VERSION 5.8 ;
BUSBITCHARS "[]" ;
DIVIDERCHAR "/" ;
UNITS
    DATABASE MICRONS 1000 ;
END UNITS

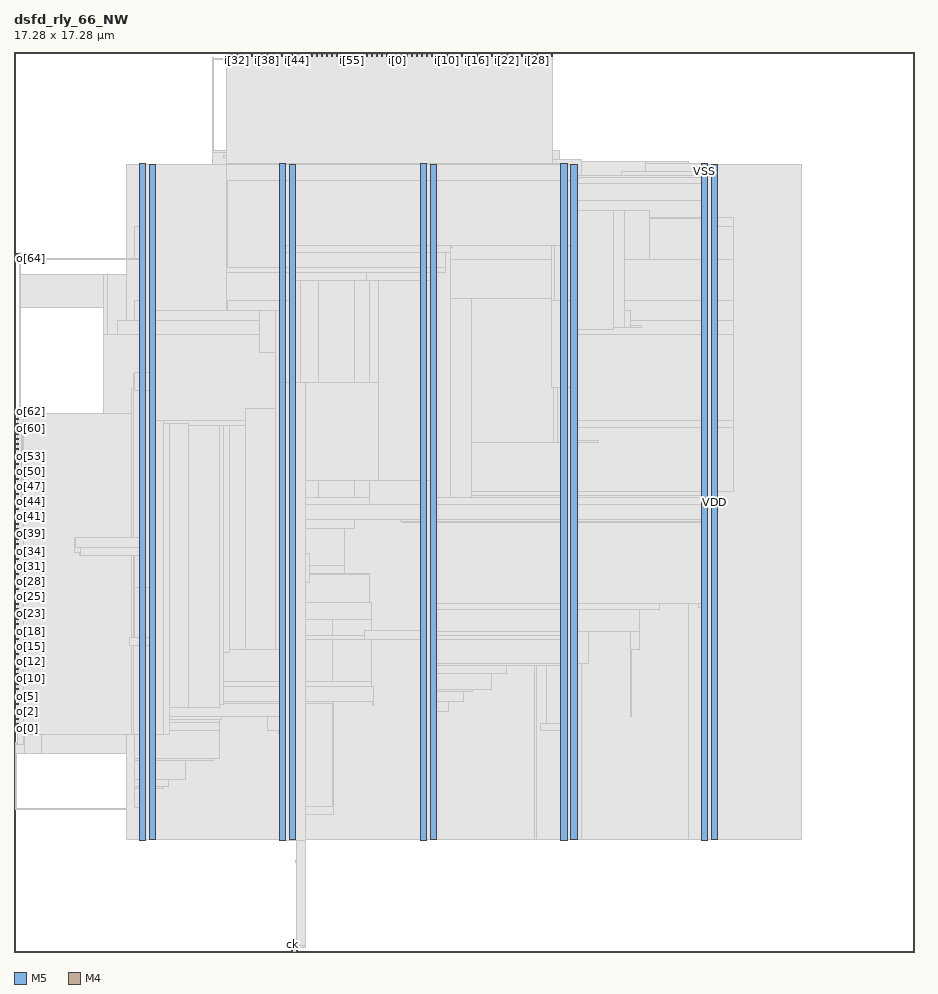
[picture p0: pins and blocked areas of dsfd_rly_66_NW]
MACRO dsfd_rly_66_NW
  FOREIGN dsfd_rly_66_NW 0 0 ;
  CLASS BLOCK ;
  SIZE 17.28 BY 17.28 ;
  PIN ck
    DIRECTION INPUT ;
    USE SIGNAL ;
    PORT
      LAYER M5 ;
        RECT  5.328 0 5.352 0.084 ;
    END
  END ck
  PIN i[0]
    DIRECTION INPUT ;
    USE SIGNAL ;
    PORT
      LAYER M5 ;
        RECT  7.344 17.196 7.368 17.28 ;
    END
  END i[0]
  PIN i[10]
    DIRECTION INPUT ;
    USE SIGNAL ;
    PORT
      LAYER M5 ;
        RECT  8.304 17.196 8.328 17.28 ;
    END
  END i[10]
  PIN i[11]
    DIRECTION INPUT ;
    USE SIGNAL ;
    PORT
      LAYER M5 ;
        RECT  8.4 17.196 8.424 17.28 ;
    END
  END i[11]
  PIN i[12]
    DIRECTION INPUT ;
    USE SIGNAL ;
    PORT
      LAYER M5 ;
        RECT  8.496 17.196 8.52 17.28 ;
    END
  END i[12]
  PIN i[13]
    DIRECTION INPUT ;
    USE SIGNAL ;
    PORT
      LAYER M5 ;
        RECT  8.592 17.196 8.616 17.28 ;
    END
  END i[13]
  PIN i[14]
    DIRECTION INPUT ;
    USE SIGNAL ;
    PORT
      LAYER M5 ;
        RECT  8.688 17.196 8.712 17.28 ;
    END
  END i[14]
  PIN i[15]
    DIRECTION INPUT ;
    USE SIGNAL ;
    PORT
      LAYER M5 ;
        RECT  8.784 17.196 8.808 17.28 ;
    END
  END i[15]
  PIN i[16]
    DIRECTION INPUT ;
    USE SIGNAL ;
    PORT
      LAYER M5 ;
        RECT  8.88 17.196 8.904 17.28 ;
    END
  END i[16]
  PIN i[17]
    DIRECTION INPUT ;
    USE SIGNAL ;
    PORT
      LAYER M5 ;
        RECT  8.976 17.196 9 17.28 ;
    END
  END i[17]
  PIN i[18]
    DIRECTION INPUT ;
    USE SIGNAL ;
    PORT
      LAYER M5 ;
        RECT  9.072 17.196 9.096 17.28 ;
    END
  END i[18]
  PIN i[19]
    DIRECTION INPUT ;
    USE SIGNAL ;
    PORT
      LAYER M5 ;
        RECT  9.168 17.196 9.192 17.28 ;
    END
  END i[19]
  PIN i[1]
    DIRECTION INPUT ;
    USE SIGNAL ;
    PORT
      LAYER M5 ;
        RECT  7.44 17.196 7.464 17.28 ;
    END
  END i[1]
  PIN i[20]
    DIRECTION INPUT ;
    USE SIGNAL ;
    PORT
      LAYER M5 ;
        RECT  9.264 17.196 9.288 17.28 ;
    END
  END i[20]
  PIN i[21]
    DIRECTION INPUT ;
    USE SIGNAL ;
    PORT
      LAYER M5 ;
        RECT  9.36 17.196 9.384 17.28 ;
    END
  END i[21]
  PIN i[22]
    DIRECTION INPUT ;
    USE SIGNAL ;
    PORT
      LAYER M5 ;
        RECT  9.456 17.196 9.48 17.28 ;
    END
  END i[22]
  PIN i[23]
    DIRECTION INPUT ;
    USE SIGNAL ;
    PORT
      LAYER M5 ;
        RECT  9.552 17.196 9.576 17.28 ;
    END
  END i[23]
  PIN i[24]
    DIRECTION INPUT ;
    USE SIGNAL ;
    PORT
      LAYER M5 ;
        RECT  9.648 17.196 9.672 17.28 ;
    END
  END i[24]
  PIN i[25]
    DIRECTION INPUT ;
    USE SIGNAL ;
    PORT
      LAYER M5 ;
        RECT  9.744 17.196 9.768 17.28 ;
    END
  END i[25]
  PIN i[26]
    DIRECTION INPUT ;
    USE SIGNAL ;
    PORT
      LAYER M5 ;
        RECT  9.84 17.196 9.864 17.28 ;
    END
  END i[26]
  PIN i[27]
    DIRECTION INPUT ;
    USE SIGNAL ;
    PORT
      LAYER M5 ;
        RECT  9.936 17.196 9.96 17.28 ;
    END
  END i[27]
  PIN i[28]
    DIRECTION INPUT ;
    USE SIGNAL ;
    PORT
      LAYER M5 ;
        RECT  10.032 17.196 10.056 17.28 ;
    END
  END i[28]
  PIN i[29]
    DIRECTION INPUT ;
    USE SIGNAL ;
    PORT
      LAYER M5 ;
        RECT  10.128 17.196 10.152 17.28 ;
    END
  END i[29]
  PIN i[2]
    DIRECTION INPUT ;
    USE SIGNAL ;
    PORT
      LAYER M5 ;
        RECT  7.536 17.196 7.56 17.28 ;
    END
  END i[2]
  PIN i[30]
    DIRECTION INPUT ;
    USE SIGNAL ;
    PORT
      LAYER M5 ;
        RECT  10.224 17.196 10.248 17.28 ;
    END
  END i[30]
  PIN i[31]
    DIRECTION INPUT ;
    USE SIGNAL ;
    PORT
      LAYER M5 ;
        RECT  10.32 17.196 10.344 17.28 ;
    END
  END i[31]
  PIN i[32]
    DIRECTION INPUT ;
    USE SIGNAL ;
    PORT
      LAYER M5 ;
        RECT  4.272 17.196 4.296 17.28 ;
    END
  END i[32]
  PIN i[33]
    DIRECTION INPUT ;
    USE SIGNAL ;
    PORT
      LAYER M5 ;
        RECT  4.368 17.196 4.392 17.28 ;
    END
  END i[33]
  PIN i[34]
    DIRECTION INPUT ;
    USE SIGNAL ;
    PORT
      LAYER M5 ;
        RECT  4.464 17.196 4.488 17.28 ;
    END
  END i[34]
  PIN i[35]
    DIRECTION INPUT ;
    USE SIGNAL ;
    PORT
      LAYER M5 ;
        RECT  4.56 17.196 4.584 17.28 ;
    END
  END i[35]
  PIN i[36]
    DIRECTION INPUT ;
    USE SIGNAL ;
    PORT
      LAYER M5 ;
        RECT  4.656 17.196 4.68 17.28 ;
    END
  END i[36]
  PIN i[37]
    DIRECTION INPUT ;
    USE SIGNAL ;
    PORT
      LAYER M5 ;
        RECT  4.752 17.196 4.776 17.28 ;
    END
  END i[37]
  PIN i[38]
    DIRECTION INPUT ;
    USE SIGNAL ;
    PORT
      LAYER M5 ;
        RECT  4.848 17.196 4.872 17.28 ;
    END
  END i[38]
  PIN i[39]
    DIRECTION INPUT ;
    USE SIGNAL ;
    PORT
      LAYER M5 ;
        RECT  4.944 17.196 4.968 17.28 ;
    END
  END i[39]
  PIN i[3]
    DIRECTION INPUT ;
    USE SIGNAL ;
    PORT
      LAYER M5 ;
        RECT  7.632 17.196 7.656 17.28 ;
    END
  END i[3]
  PIN i[40]
    DIRECTION INPUT ;
    USE SIGNAL ;
    PORT
      LAYER M5 ;
        RECT  5.04 17.196 5.064 17.28 ;
    END
  END i[40]
  PIN i[41]
    DIRECTION INPUT ;
    USE SIGNAL ;
    PORT
      LAYER M5 ;
        RECT  5.136 17.196 5.16 17.28 ;
    END
  END i[41]
  PIN i[42]
    DIRECTION INPUT ;
    USE SIGNAL ;
    PORT
      LAYER M5 ;
        RECT  5.232 17.196 5.256 17.28 ;
    END
  END i[42]
  PIN i[43]
    DIRECTION INPUT ;
    USE SIGNAL ;
    PORT
      LAYER M5 ;
        RECT  5.328 17.196 5.352 17.28 ;
    END
  END i[43]
  PIN i[44]
    DIRECTION INPUT ;
    USE SIGNAL ;
    PORT
      LAYER M5 ;
        RECT  5.424 17.196 5.448 17.28 ;
    END
  END i[44]
  PIN i[45]
    DIRECTION INPUT ;
    USE SIGNAL ;
    PORT
      LAYER M5 ;
        RECT  5.52 17.196 5.544 17.28 ;
    END
  END i[45]
  PIN i[46]
    DIRECTION INPUT ;
    USE SIGNAL ;
    PORT
      LAYER M5 ;
        RECT  5.616 17.196 5.64 17.28 ;
    END
  END i[46]
  PIN i[47]
    DIRECTION INPUT ;
    USE SIGNAL ;
    PORT
      LAYER M5 ;
        RECT  5.712 17.196 5.736 17.28 ;
    END
  END i[47]
  PIN i[48]
    DIRECTION INPUT ;
    USE SIGNAL ;
    PORT
      LAYER M5 ;
        RECT  5.808 17.196 5.832 17.28 ;
    END
  END i[48]
  PIN i[49]
    DIRECTION INPUT ;
    USE SIGNAL ;
    PORT
      LAYER M5 ;
        RECT  5.904 17.196 5.928 17.28 ;
    END
  END i[49]
  PIN i[4]
    DIRECTION INPUT ;
    USE SIGNAL ;
    PORT
      LAYER M5 ;
        RECT  7.728 17.196 7.752 17.28 ;
    END
  END i[4]
  PIN i[50]
    DIRECTION INPUT ;
    USE SIGNAL ;
    PORT
      LAYER M5 ;
        RECT  6 17.196 6.024 17.28 ;
    END
  END i[50]
  PIN i[51]
    DIRECTION INPUT ;
    USE SIGNAL ;
    PORT
      LAYER M5 ;
        RECT  6.096 17.196 6.12 17.28 ;
    END
  END i[51]
  PIN i[52]
    DIRECTION INPUT ;
    USE SIGNAL ;
    PORT
      LAYER M5 ;
        RECT  6.192 17.196 6.216 17.28 ;
    END
  END i[52]
  PIN i[53]
    DIRECTION INPUT ;
    USE SIGNAL ;
    PORT
      LAYER M5 ;
        RECT  6.288 17.196 6.312 17.28 ;
    END
  END i[53]
  PIN i[54]
    DIRECTION INPUT ;
    USE SIGNAL ;
    PORT
      LAYER M5 ;
        RECT  6.384 17.196 6.408 17.28 ;
    END
  END i[54]
  PIN i[55]
    DIRECTION INPUT ;
    USE SIGNAL ;
    PORT
      LAYER M5 ;
        RECT  6.48 17.196 6.504 17.28 ;
    END
  END i[55]
  PIN i[56]
    DIRECTION INPUT ;
    USE SIGNAL ;
    PORT
      LAYER M5 ;
        RECT  6.576 17.196 6.6 17.28 ;
    END
  END i[56]
  PIN i[57]
    DIRECTION INPUT ;
    USE SIGNAL ;
    PORT
      LAYER M5 ;
        RECT  6.672 17.196 6.696 17.28 ;
    END
  END i[57]
  PIN i[58]
    DIRECTION INPUT ;
    USE SIGNAL ;
    PORT
      LAYER M5 ;
        RECT  6.768 17.196 6.792 17.28 ;
    END
  END i[58]
  PIN i[59]
    DIRECTION INPUT ;
    USE SIGNAL ;
    PORT
      LAYER M5 ;
        RECT  6.864 17.196 6.888 17.28 ;
    END
  END i[59]
  PIN i[5]
    DIRECTION INPUT ;
    USE SIGNAL ;
    PORT
      LAYER M5 ;
        RECT  7.824 17.196 7.848 17.28 ;
    END
  END i[5]
  PIN i[60]
    DIRECTION INPUT ;
    USE SIGNAL ;
    PORT
      LAYER M5 ;
        RECT  6.96 17.196 6.984 17.28 ;
    END
  END i[60]
  PIN i[61]
    DIRECTION INPUT ;
    USE SIGNAL ;
    PORT
      LAYER M5 ;
        RECT  7.056 17.196 7.08 17.28 ;
    END
  END i[61]
  PIN i[62]
    DIRECTION INPUT ;
    USE SIGNAL ;
    PORT
      LAYER M5 ;
        RECT  7.152 17.196 7.176 17.28 ;
    END
  END i[62]
  PIN i[63]
    DIRECTION INPUT ;
    USE SIGNAL ;
    PORT
      LAYER M5 ;
        RECT  7.248 17.196 7.272 17.28 ;
    END
  END i[63]
  PIN i[64]
    DIRECTION INPUT ;
    USE SIGNAL ;
    PORT
      LAYER M5 ;
        RECT  4.08 17.196 4.104 17.28 ;
    END
  END i[64]
  PIN i[65]
    DIRECTION INPUT ;
    USE SIGNAL ;
    PORT
      LAYER M5 ;
        RECT  4.176 17.196 4.2 17.28 ;
    END
  END i[65]
  PIN i[6]
    DIRECTION INPUT ;
    USE SIGNAL ;
    PORT
      LAYER M5 ;
        RECT  7.92 17.196 7.944 17.28 ;
    END
  END i[6]
  PIN i[7]
    DIRECTION INPUT ;
    USE SIGNAL ;
    PORT
      LAYER M5 ;
        RECT  8.016 17.196 8.04 17.28 ;
    END
  END i[7]
  PIN i[8]
    DIRECTION INPUT ;
    USE SIGNAL ;
    PORT
      LAYER M5 ;
        RECT  8.112 17.196 8.136 17.28 ;
    END
  END i[8]
  PIN i[9]
    DIRECTION INPUT ;
    USE SIGNAL ;
    PORT
      LAYER M5 ;
        RECT  8.208 17.196 8.232 17.28 ;
    END
  END i[9]
  PIN o[0]
    DIRECTION OUTPUT ;
    USE SIGNAL ;
    PORT
      LAYER M4 ;
        RECT  0 4.272 0.084 4.296 ;
    END
  END o[0]
  PIN o[10]
    DIRECTION OUTPUT ;
    USE SIGNAL ;
    PORT
      LAYER M4 ;
        RECT  0 5.232 0.084 5.256 ;
    END
  END o[10]
  PIN o[11]
    DIRECTION OUTPUT ;
    USE SIGNAL ;
    PORT
      LAYER M4 ;
        RECT  0 5.328 0.084 5.352 ;
    END
  END o[11]
  PIN o[12]
    DIRECTION OUTPUT ;
    USE SIGNAL ;
    PORT
      LAYER M4 ;
        RECT  0 5.424 0.084 5.448 ;
    END
  END o[12]
  PIN o[13]
    DIRECTION OUTPUT ;
    USE SIGNAL ;
    PORT
      LAYER M4 ;
        RECT  0 5.52 0.084 5.544 ;
    END
  END o[13]
  PIN o[14]
    DIRECTION OUTPUT ;
    USE SIGNAL ;
    PORT
      LAYER M4 ;
        RECT  0 5.616 0.084 5.64 ;
    END
  END o[14]
  PIN o[15]
    DIRECTION OUTPUT ;
    USE SIGNAL ;
    PORT
      LAYER M4 ;
        RECT  0 5.712 0.084 5.736 ;
    END
  END o[15]
  PIN o[16]
    DIRECTION OUTPUT ;
    USE SIGNAL ;
    PORT
      LAYER M4 ;
        RECT  0 5.808 0.084 5.832 ;
    END
  END o[16]
  PIN o[17]
    DIRECTION OUTPUT ;
    USE SIGNAL ;
    PORT
      LAYER M4 ;
        RECT  0 5.904 0.084 5.928 ;
    END
  END o[17]
  PIN o[18]
    DIRECTION OUTPUT ;
    USE SIGNAL ;
    PORT
      LAYER M4 ;
        RECT  0 6 0.084 6.024 ;
    END
  END o[18]
  PIN o[19]
    DIRECTION OUTPUT ;
    USE SIGNAL ;
    PORT
      LAYER M4 ;
        RECT  0 6.096 0.084 6.12 ;
    END
  END o[19]
  PIN o[1]
    DIRECTION OUTPUT ;
    USE SIGNAL ;
    PORT
      LAYER M4 ;
        RECT  0 4.368 0.084 4.392 ;
    END
  END o[1]
  PIN o[20]
    DIRECTION OUTPUT ;
    USE SIGNAL ;
    PORT
      LAYER M4 ;
        RECT  0 6.192 0.084 6.216 ;
    END
  END o[20]
  PIN o[21]
    DIRECTION OUTPUT ;
    USE SIGNAL ;
    PORT
      LAYER M4 ;
        RECT  0 6.288 0.084 6.312 ;
    END
  END o[21]
  PIN o[22]
    DIRECTION OUTPUT ;
    USE SIGNAL ;
    PORT
      LAYER M4 ;
        RECT  0 6.384 0.084 6.408 ;
    END
  END o[22]
  PIN o[23]
    DIRECTION OUTPUT ;
    USE SIGNAL ;
    PORT
      LAYER M4 ;
        RECT  0 6.48 0.084 6.504 ;
    END
  END o[23]
  PIN o[24]
    DIRECTION OUTPUT ;
    USE SIGNAL ;
    PORT
      LAYER M4 ;
        RECT  0 6.576 0.084 6.6 ;
    END
  END o[24]
  PIN o[25]
    DIRECTION OUTPUT ;
    USE SIGNAL ;
    PORT
      LAYER M4 ;
        RECT  0 6.672 0.084 6.696 ;
    END
  END o[25]
  PIN o[26]
    DIRECTION OUTPUT ;
    USE SIGNAL ;
    PORT
      LAYER M4 ;
        RECT  0 6.768 0.084 6.792 ;
    END
  END o[26]
  PIN o[27]
    DIRECTION OUTPUT ;
    USE SIGNAL ;
    PORT
      LAYER M4 ;
        RECT  0 6.864 0.084 6.888 ;
    END
  END o[27]
  PIN o[28]
    DIRECTION OUTPUT ;
    USE SIGNAL ;
    PORT
      LAYER M4 ;
        RECT  0 6.96 0.084 6.984 ;
    END
  END o[28]
  PIN o[29]
    DIRECTION OUTPUT ;
    USE SIGNAL ;
    PORT
      LAYER M4 ;
        RECT  0 7.056 0.084 7.08 ;
    END
  END o[29]
  PIN o[2]
    DIRECTION OUTPUT ;
    USE SIGNAL ;
    PORT
      LAYER M4 ;
        RECT  0 4.464 0.084 4.488 ;
    END
  END o[2]
  PIN o[30]
    DIRECTION OUTPUT ;
    USE SIGNAL ;
    PORT
      LAYER M4 ;
        RECT  0 7.152 0.084 7.176 ;
    END
  END o[30]
  PIN o[31]
    DIRECTION OUTPUT ;
    USE SIGNAL ;
    PORT
      LAYER M4 ;
        RECT  0 7.248 0.084 7.272 ;
    END
  END o[31]
  PIN o[32]
    DIRECTION OUTPUT ;
    USE SIGNAL ;
    PORT
      LAYER M4 ;
        RECT  0 7.344 0.084 7.368 ;
    END
  END o[32]
  PIN o[33]
    DIRECTION OUTPUT ;
    USE SIGNAL ;
    PORT
      LAYER M4 ;
        RECT  0 7.44 0.084 7.464 ;
    END
  END o[33]
  PIN o[34]
    DIRECTION OUTPUT ;
    USE SIGNAL ;
    PORT
      LAYER M4 ;
        RECT  0 7.536 0.084 7.56 ;
    END
  END o[34]
  PIN o[35]
    DIRECTION OUTPUT ;
    USE SIGNAL ;
    PORT
      LAYER M4 ;
        RECT  0 7.632 0.084 7.656 ;
    END
  END o[35]
  PIN o[36]
    DIRECTION OUTPUT ;
    USE SIGNAL ;
    PORT
      LAYER M4 ;
        RECT  0 7.728 0.084 7.752 ;
    END
  END o[36]
  PIN o[37]
    DIRECTION OUTPUT ;
    USE SIGNAL ;
    PORT
      LAYER M4 ;
        RECT  0 7.824 0.084 7.848 ;
    END
  END o[37]
  PIN o[38]
    DIRECTION OUTPUT ;
    USE SIGNAL ;
    PORT
      LAYER M4 ;
        RECT  0 7.92 0.084 7.944 ;
    END
  END o[38]
  PIN o[39]
    DIRECTION OUTPUT ;
    USE SIGNAL ;
    PORT
      LAYER M4 ;
        RECT  0 8.016 0.084 8.04 ;
    END
  END o[39]
  PIN o[3]
    DIRECTION OUTPUT ;
    USE SIGNAL ;
    PORT
      LAYER M4 ;
        RECT  0 4.56 0.084 4.584 ;
    END
  END o[3]
  PIN o[40]
    DIRECTION OUTPUT ;
    USE SIGNAL ;
    PORT
      LAYER M4 ;
        RECT  0 8.112 0.084 8.136 ;
    END
  END o[40]
  PIN o[41]
    DIRECTION OUTPUT ;
    USE SIGNAL ;
    PORT
      LAYER M4 ;
        RECT  0 8.208 0.084 8.232 ;
    END
  END o[41]
  PIN o[42]
    DIRECTION OUTPUT ;
    USE SIGNAL ;
    PORT
      LAYER M4 ;
        RECT  0 8.304 0.084 8.328 ;
    END
  END o[42]
  PIN o[43]
    DIRECTION OUTPUT ;
    USE SIGNAL ;
    PORT
      LAYER M4 ;
        RECT  0 8.4 0.084 8.424 ;
    END
  END o[43]
  PIN o[44]
    DIRECTION OUTPUT ;
    USE SIGNAL ;
    PORT
      LAYER M4 ;
        RECT  0 8.496 0.084 8.52 ;
    END
  END o[44]
  PIN o[45]
    DIRECTION OUTPUT ;
    USE SIGNAL ;
    PORT
      LAYER M4 ;
        RECT  0 8.592 0.084 8.616 ;
    END
  END o[45]
  PIN o[46]
    DIRECTION OUTPUT ;
    USE SIGNAL ;
    PORT
      LAYER M4 ;
        RECT  0 8.688 0.084 8.712 ;
    END
  END o[46]
  PIN o[47]
    DIRECTION OUTPUT ;
    USE SIGNAL ;
    PORT
      LAYER M4 ;
        RECT  0 8.784 0.084 8.808 ;
    END
  END o[47]
  PIN o[48]
    DIRECTION OUTPUT ;
    USE SIGNAL ;
    PORT
      LAYER M4 ;
        RECT  0 8.88 0.084 8.904 ;
    END
  END o[48]
  PIN o[49]
    DIRECTION OUTPUT ;
    USE SIGNAL ;
    PORT
      LAYER M4 ;
        RECT  0 8.976 0.084 9 ;
    END
  END o[49]
  PIN o[4]
    DIRECTION OUTPUT ;
    USE SIGNAL ;
    PORT
      LAYER M4 ;
        RECT  0 4.656 0.084 4.68 ;
    END
  END o[4]
  PIN o[50]
    DIRECTION OUTPUT ;
    USE SIGNAL ;
    PORT
      LAYER M4 ;
        RECT  0 9.072 0.084 9.096 ;
    END
  END o[50]
  PIN o[51]
    DIRECTION OUTPUT ;
    USE SIGNAL ;
    PORT
      LAYER M4 ;
        RECT  0 9.168 0.084 9.192 ;
    END
  END o[51]
  PIN o[52]
    DIRECTION OUTPUT ;
    USE SIGNAL ;
    PORT
      LAYER M4 ;
        RECT  0 9.264 0.084 9.288 ;
    END
  END o[52]
  PIN o[53]
    DIRECTION OUTPUT ;
    USE SIGNAL ;
    PORT
      LAYER M4 ;
        RECT  0 9.36 0.084 9.384 ;
    END
  END o[53]
  PIN o[54]
    DIRECTION OUTPUT ;
    USE SIGNAL ;
    PORT
      LAYER M4 ;
        RECT  0 9.456 0.084 9.48 ;
    END
  END o[54]
  PIN o[55]
    DIRECTION OUTPUT ;
    USE SIGNAL ;
    PORT
      LAYER M4 ;
        RECT  0 9.552 0.084 9.576 ;
    END
  END o[55]
  PIN o[56]
    DIRECTION OUTPUT ;
    USE SIGNAL ;
    PORT
      LAYER M4 ;
        RECT  0 9.648 0.084 9.672 ;
    END
  END o[56]
  PIN o[57]
    DIRECTION OUTPUT ;
    USE SIGNAL ;
    PORT
      LAYER M4 ;
        RECT  0 9.744 0.084 9.768 ;
    END
  END o[57]
  PIN o[58]
    DIRECTION OUTPUT ;
    USE SIGNAL ;
    PORT
      LAYER M4 ;
        RECT  0 9.84 0.084 9.864 ;
    END
  END o[58]
  PIN o[59]
    DIRECTION OUTPUT ;
    USE SIGNAL ;
    PORT
      LAYER M4 ;
        RECT  0 9.936 0.084 9.96 ;
    END
  END o[59]
  PIN o[5]
    DIRECTION OUTPUT ;
    USE SIGNAL ;
    PORT
      LAYER M4 ;
        RECT  0 4.752 0.084 4.776 ;
    END
  END o[5]
  PIN o[60]
    DIRECTION OUTPUT ;
    USE SIGNAL ;
    PORT
      LAYER M4 ;
        RECT  0 10.032 0.084 10.056 ;
    END
  END o[60]
  PIN o[61]
    DIRECTION OUTPUT ;
    USE SIGNAL ;
    PORT
      LAYER M4 ;
        RECT  0 10.128 0.084 10.152 ;
    END
  END o[61]
  PIN o[62]
    DIRECTION OUTPUT ;
    USE SIGNAL ;
    PORT
      LAYER M4 ;
        RECT  0 10.224 0.084 10.248 ;
    END
  END o[62]
  PIN o[63]
    DIRECTION OUTPUT ;
    USE SIGNAL ;
    PORT
      LAYER M4 ;
        RECT  0 10.32 0.084 10.344 ;
    END
  END o[63]
  PIN o[64]
    DIRECTION OUTPUT ;
    USE SIGNAL ;
    PORT
      LAYER M4 ;
        RECT  0 13.296 0.084 13.32 ;
    END
  END o[64]
  PIN o[65]
    DIRECTION OUTPUT ;
    USE SIGNAL ;
    PORT
      LAYER M4 ;
        RECT  0 13.392 0.084 13.416 ;
    END
  END o[65]
  PIN o[6]
    DIRECTION OUTPUT ;
    USE SIGNAL ;
    PORT
      LAYER M4 ;
        RECT  0 4.848 0.084 4.872 ;
    END
  END o[6]
  PIN o[7]
    DIRECTION OUTPUT ;
    USE SIGNAL ;
    PORT
      LAYER M4 ;
        RECT  0 4.944 0.084 4.968 ;
    END
  END o[7]
  PIN o[8]
    DIRECTION OUTPUT ;
    USE SIGNAL ;
    PORT
      LAYER M4 ;
        RECT  0 5.04 0.084 5.064 ;
    END
  END o[8]
  PIN o[9]
    DIRECTION OUTPUT ;
    USE SIGNAL ;
    PORT
      LAYER M4 ;
        RECT  0 5.136 0.084 5.16 ;
    END
  END o[9]
  PIN rs
    DIRECTION INPUT ;
    USE SIGNAL ;
    PORT
      LAYER M5 ;
        RECT  5.424 0 5.448 0.084 ;
    END
  END rs
  PIN VDD
    DIRECTION INOUT ;
    USE POWER ;
    PORT
      LAYER M5 ;
        RECT  13.392 2.151 13.512 15.129 ;
        RECT  10.692 2.151 10.812 15.129 ;
        RECT  7.992 2.151 8.112 15.129 ;
        RECT  5.292 2.151 5.412 15.129 ;
        RECT  2.592 2.151 2.712 15.129 ;
    END
  END VDD
  PIN VSS
    DIRECTION INOUT ;
    USE GROUND ;
    PORT
      LAYER M5 ;
        RECT  13.2 2.137 13.32 15.143 ;
        RECT  10.5 2.137 10.62 15.143 ;
        RECT  7.8 2.137 7.92 15.143 ;
        RECT  5.1 2.137 5.22 15.143 ;
        RECT  2.4 2.137 2.52 15.143 ;
    END
  END VSS
  # OT_OBS_CLOSED layer=M5 d_um=1.536 added=9
  OBS
    LAYER RVTN ;
     RECT  2.16 2.16 15.12 2.295 ;
     RECT  2.16 2.565 15.12 2.835 ;
     RECT  2.16 3.105 15.12 3.375 ;
     RECT  2.16 3.645 15.12 3.915 ;
     RECT  2.16 4.185 15.12 4.455 ;
     RECT  2.16 4.725 15.12 4.995 ;
     RECT  2.16 5.265 15.12 5.535 ;
     RECT  2.16 5.805 15.12 6.075 ;
     RECT  2.16 6.345 15.12 6.615 ;
     RECT  2.16 6.885 15.12 7.155 ;
     RECT  2.16 7.425 15.12 7.695 ;
     RECT  2.16 7.965 15.12 8.235 ;
     RECT  2.16 8.505 15.12 8.775 ;
     RECT  2.16 9.045 15.12 9.315 ;
     RECT  2.16 9.585 15.12 9.855 ;
     RECT  2.16 10.125 15.12 10.395 ;
     RECT  2.16 10.665 15.12 10.935 ;
     RECT  2.16 11.205 15.12 11.475 ;
     RECT  2.16 11.745 15.12 12.015 ;
     RECT  2.16 12.285 15.12 12.555 ;
     RECT  2.16 12.825 15.12 13.095 ;
     RECT  2.16 13.365 15.12 13.635 ;
     RECT  2.16 13.905 15.12 14.175 ;
     RECT  2.16 14.445 15.12 14.715 ;
     RECT  2.16 14.985 15.12 15.12 ;
    LAYER RVTP ;
     RECT  2.16 2.295 15.12 2.565 ;
     RECT  2.16 2.835 15.12 3.105 ;
     RECT  2.16 3.375 15.12 3.645 ;
     RECT  2.16 3.915 15.12 4.185 ;
     RECT  2.16 4.455 15.12 4.725 ;
     RECT  2.16 4.995 15.12 5.265 ;
     RECT  2.16 5.535 15.12 5.805 ;
     RECT  2.16 6.075 15.12 6.345 ;
     RECT  2.16 6.615 15.12 6.885 ;
     RECT  2.16 7.155 15.12 7.425 ;
     RECT  2.16 7.695 15.12 7.965 ;
     RECT  2.16 8.235 15.12 8.505 ;
     RECT  2.16 8.775 15.12 9.045 ;
     RECT  2.16 9.315 15.12 9.585 ;
     RECT  2.16 9.855 15.12 10.125 ;
     RECT  2.16 10.395 15.12 10.665 ;
     RECT  2.16 10.935 15.12 11.205 ;
     RECT  2.16 11.475 15.12 11.745 ;
     RECT  2.16 12.015 15.12 12.285 ;
     RECT  2.16 12.555 15.12 12.825 ;
     RECT  2.16 13.095 15.12 13.365 ;
     RECT  2.16 13.635 15.12 13.905 ;
     RECT  2.16 14.175 15.12 14.445 ;
     RECT  2.16 14.715 15.12 14.985 ;
    LAYER M1 ;
     RECT  2.16 2.151 15.12 15.129 ;
    LAYER M2 ;
     RECT  0.103 5.931 0.203 6.678 ;
     RECT  0.175 3.816 0.211 3.834 ;
     RECT  0.211 9.36 0.347 9.378 ;
     RECT  0.211 3.816 0.535 4.212 ;
     RECT  0.103 12.366 1.723 13.014 ;
     RECT  1.723 11.826 1.795 13.014 ;
     RECT  0.031 2.736 2.16 2.754 ;
     RECT  0.535 3.816 2.16 4.554 ;
     RECT  0.535 6.696 2.16 6.714 ;
     RECT  1.759 10.476 2.16 10.494 ;
     RECT  1.795 11.556 2.16 13.014 ;
     RECT  2.16 2.151 10.003 15.129 ;
     RECT  10.003 2.151 10.039 15.174 ;
     RECT  10.039 2.151 10.895 15.21 ;
     RECT  10.895 2.151 12.947 15.174 ;
     RECT  12.947 2.151 15.12 15.129 ;
    LAYER M3 ;
     RECT  5.472 1.723 5.49 2.143 ;
     RECT  2.415 2.143 2.505 2.413 ;
     RECT  7.815 2.143 7.905 2.413 ;
     RECT  10.515 2.143 10.605 2.413 ;
     RECT  13.215 2.143 13.305 2.413 ;
     RECT  5.115 2.143 5.49 2.605 ;
     RECT  5.115 2.605 5.562 2.641 ;
     RECT  2.415 2.413 2.697 2.767 ;
     RECT  5.115 2.641 6.138 2.795 ;
     RECT  2.304 2.767 2.697 3.145 ;
     RECT  2.304 3.145 2.862 3.181 ;
     RECT  2.304 3.181 2.97 3.307 ;
     RECT  2.304 3.307 3.294 3.685 ;
     RECT  2.304 3.685 3.834 3.721 ;
     RECT  0.036 2.731 0.054 3.811 ;
     RECT  0.036 3.811 0.198 4.013 ;
     RECT  0.108 4.013 0.198 4.189 ;
     RECT  5.115 2.795 5.397 4.189 ;
     RECT  2.304 3.721 3.942 4.261 ;
     RECT  5.076 4.189 5.397 4.261 ;
     RECT  10.515 2.413 10.797 4.261 ;
     RECT  0.108 4.189 0.234 4.301 ;
     RECT  10.116 4.261 10.797 4.379 ;
     RECT  2.268 4.261 3.942 4.397 ;
     RECT  2.304 4.397 3.942 4.459 ;
     RECT  0.144 4.301 0.234 4.531 ;
     RECT  2.304 4.459 3.978 4.531 ;
     RECT  4.86 4.261 5.397 4.531 ;
     RECT  7.815 2.413 8.097 4.621 ;
     RECT  2.304 4.531 5.397 4.765 ;
     RECT  6.12 2.795 6.138 4.765 ;
     RECT  2.304 4.765 6.138 4.801 ;
     RECT  6.876 4.729 6.894 4.801 ;
     RECT  7.815 4.621 8.334 4.801 ;
     RECT  7.815 4.801 8.622 4.999 ;
     RECT  7.815 4.999 8.802 5.035 ;
     RECT  2.304 4.801 6.894 5.099 ;
     RECT  2.304 5.099 6.858 5.189 ;
     RECT  7.815 5.035 9.162 5.341 ;
     RECT  7.815 5.341 9.45 5.503 ;
     RECT  10.224 4.379 10.797 5.503 ;
     RECT  7.815 5.503 10.797 5.539 ;
     RECT  0.144 4.531 0.558 5.645 ;
     RECT  11.844 4.531 11.862 5.809 ;
     RECT  0.144 5.645 0.234 5.926 ;
     RECT  7.815 5.539 11.034 6.151 ;
     RECT  11.844 5.809 12.006 6.151 ;
     RECT  2.304 5.189 5.397 6.385 ;
     RECT  6.12 5.189 6.858 6.385 ;
     RECT  7.815 6.151 12.006 6.583 ;
     RECT  13.215 2.413 13.497 6.619 ;
     RECT  0.108 5.926 0.234 6.691 ;
     RECT  7.815 6.583 12.402 6.691 ;
     RECT  13.14 6.619 13.497 6.691 ;
     RECT  2.304 6.385 6.858 6.719 ;
     RECT  0.108 6.691 0.558 6.797 ;
     RECT  0.18 6.797 0.558 6.845 ;
     RECT  0.54 6.845 0.558 6.893 ;
     RECT  1.152 6.907 1.17 7.051 ;
     RECT  2.304 6.719 6.822 7.243 ;
     RECT  2.268 7.243 6.822 7.259 ;
     RECT  2.268 7.259 6.354 7.421 ;
     RECT  1.152 7.051 1.278 7.531 ;
     RECT  1.152 7.531 1.386 7.661 ;
     RECT  1.152 7.661 1.278 7.853 ;
     RECT  0.144 7.819 0.162 8.107 ;
     RECT  2.304 7.421 6.354 8.131 ;
     RECT  7.815 6.691 13.497 8.239 ;
     RECT  7.452 8.239 13.497 8.275 ;
     RECT  2.304 8.131 6.534 8.311 ;
     RECT  7.416 8.275 13.497 8.311 ;
     RECT  1.26 7.853 1.278 8.477 ;
     RECT  2.304 8.311 13.497 8.587 ;
     RECT  0.108 8.107 0.162 8.683 ;
     RECT  1.728 8.587 13.497 8.851 ;
     RECT  1.728 8.851 13.806 10.075 ;
     RECT  0.108 8.683 0.342 10.157 ;
     RECT  1.152 10.075 13.806 10.205 ;
     RECT  0.108 10.157 0.234 10.253 ;
     RECT  1.728 10.205 13.806 11.849 ;
     RECT  1.98 11.849 13.806 12.119 ;
     RECT  2.304 12.119 13.806 12.515 ;
     RECT  2.412 12.515 13.806 13.291 ;
     RECT  0.108 10.253 0.126 13.421 ;
     RECT  2.304 13.291 13.806 13.937 ;
     RECT  2.412 13.937 13.806 14.099 ;
     RECT  2.412 14.099 13.497 14.429 ;
     RECT  2.415 14.429 13.497 14.747 ;
     RECT  2.415 14.747 2.697 14.867 ;
     RECT  3.42 14.747 13.497 14.867 ;
     RECT  3.42 14.867 13.305 14.909 ;
     RECT  11.664 14.909 13.305 14.981 ;
     RECT  2.415 14.867 2.505 15.137 ;
     RECT  12.132 14.981 13.305 15.137 ;
     RECT  12.132 15.137 12.942 15.179 ;
     RECT  7.38 14.909 10.89 15.215 ;
     RECT  7.38 15.215 10.458 15.293 ;
     RECT  3.816 14.909 6.642 15.341 ;
     RECT  3.816 15.341 5.274 15.389 ;
     RECT  7.38 15.293 7.398 15.389 ;
     RECT  8.532 15.293 10.458 15.389 ;
     RECT  6.012 15.341 6.642 16.459 ;
     RECT  6.012 16.459 6.894 16.589 ;
     RECT  6.876 16.589 6.894 16.637 ;
     RECT  7.092 16.891 7.11 17.069 ;
     RECT  3.816 15.389 3.834 17.165 ;
     RECT  6.012 16.589 6.03 17.165 ;
    LAYER M4 ;
     RECT  0.025 3.984 0.06 4.008 ;
     RECT  0.06 13.296 0.137 13.416 ;
     RECT  0.06 3.984 0.173 10.344 ;
     RECT  0.173 4.176 2.252 10.344 ;
     RECT  2.252 4.176 2.285 10.824 ;
     RECT  2.285 4.176 2.408 11.112 ;
     RECT  0.137 13.296 2.408 13.32 ;
     RECT  2.401 14.4 2.408 14.424 ;
     RECT  2.408 2.148 2.512 15.132 ;
     RECT  2.512 2.418 2.704 14.862 ;
     RECT  2.704 4.176 2.873 10.2 ;
     RECT  2.873 4.176 2.981 10.152 ;
     RECT  2.704 13.008 3.197 14.424 ;
     RECT  2.981 4.704 3.341 10.152 ;
     RECT  3.341 4.704 3.953 10.104 ;
     RECT  3.953 4.752 4.025 10.104 ;
     RECT  3.197 13.008 4.028 14.136 ;
     RECT  4.021 15.264 4.129 15.288 ;
     RECT  4.025 5.76 4.133 10.104 ;
     RECT  3.805 17.136 4.211 17.16 ;
     RECT  4.129 15.264 4.229 15.336 ;
     RECT  4.133 5.808 4.453 10.104 ;
     RECT  4.028 12.336 4.7 14.136 ;
     RECT  4.229 15.264 4.7 15.384 ;
     RECT  4.7 12.336 4.705 15.384 ;
     RECT  4.453 5.808 5.029 10.44 ;
     RECT  4.705 11.52 5.029 15.384 ;
     RECT  5.029 5.808 5.108 15.384 ;
     RECT  5.108 2.148 5.404 15.384 ;
     RECT  5.413 1.728 5.501 1.752 ;
     RECT  5.404 7.104 5.501 15.384 ;
     RECT  5.317 0.096 5.603 0.12 ;
     RECT  5.501 7.104 5.681 7.656 ;
     RECT  5.501 8.736 5.843 15.384 ;
     RECT  5.317 17.136 6.041 17.16 ;
     RECT  5.843 15.264 6.113 15.384 ;
     RECT  6.113 15.264 6.149 15.288 ;
     RECT  5.843 8.736 6.545 13.992 ;
     RECT  5.404 6 6.721 6.072 ;
     RECT  6.545 8.736 6.829 13.704 ;
     RECT  6.613 16.56 6.86 16.632 ;
     RECT  6.86 16.464 6.947 16.632 ;
     RECT  6.947 16.56 6.995 16.632 ;
     RECT  7.153 14.784 7.325 14.808 ;
     RECT  7.325 14.784 7.409 15.384 ;
     RECT  7.037 16.896 7.525 17.064 ;
     RECT  6.721 6 7.808 6.168 ;
     RECT  6.829 8.592 7.808 13.704 ;
     RECT  7.409 14.784 7.808 15.288 ;
     RECT  7.525 16.896 7.859 17.112 ;
     RECT  7.808 2.148 7.912 15.288 ;
     RECT  7.912 2.418 8.104 15.288 ;
     RECT  7.859 16.992 8.291 17.112 ;
     RECT  8.104 8.736 8.387 13.704 ;
     RECT  8.291 16.992 8.387 17.016 ;
     RECT  8.387 13.536 8.417 13.704 ;
     RECT  8.104 14.832 8.477 15.288 ;
     RECT  8.387 8.736 8.777 12.552 ;
     RECT  8.477 14.832 8.819 15.384 ;
     RECT  8.417 13.584 9.173 13.704 ;
     RECT  8.819 15.264 9.925 15.384 ;
     RECT  9.173 13.584 10.349 13.656 ;
     RECT  8.777 9.792 10.357 12.552 ;
     RECT  10.349 13.584 10.357 13.704 ;
     RECT  10.357 9.792 10.429 13.704 ;
     RECT  9.925 15.216 10.469 15.384 ;
     RECT  8.104 6 10.508 6.072 ;
     RECT  8.777 8.736 10.508 8.76 ;
     RECT  10.429 9.792 10.508 13.848 ;
     RECT  10.508 2.148 10.612 15.132 ;
     RECT  10.612 2.418 10.804 14.862 ;
     RECT  10.804 9.792 11.225 9.816 ;
     RECT  10.804 11.952 11.513 14.232 ;
     RECT  11.513 12 11.729 14.232 ;
     RECT  11.729 12 11.837 12.312 ;
     RECT  11.837 12 12.053 12.024 ;
     RECT  11.729 13.296 12.197 14.232 ;
     RECT  10.804 8.736 13.208 8.76 ;
     RECT  12.197 13.296 13.208 14.088 ;
     RECT  13.208 2.148 13.312 15.132 ;
     RECT  13.312 2.418 13.504 14.862 ;
    LAYER M5 ;
     RECT  5.328 0.016 5.448 0.085 ;
     RECT  5.328 0.085 5.592 0.131 ;
     RECT  5.424 0.131 5.592 2.137 ;
     RECT  2.4 2.137 2.52 2.151 ;
     RECT  7.8 2.137 7.92 2.151 ;
     RECT  10.5 2.137 10.62 2.151 ;
     RECT  13.2 2.137 13.32 2.151 ;
     RECT  2.4 2.151 2.712 5.893 ;
     RECT  2.208 5.893 2.712 6.035 ;
     RECT  2.304 6.035 2.712 6.995 ;
     RECT  1.248 7.621 1.272 7.669 ;
     RECT  1.152 7.669 1.272 7.763 ;
     RECT  1.152 7.763 1.176 7.955 ;
     RECT  7.8 2.151 8.112 9.061 ;
     RECT  0.144 8.533 0.168 9.205 ;
     RECT  0.144 9.205 0.216 9.395 ;
     RECT  0.144 9.395 0.168 10.163 ;
     RECT  2.4 6.995 2.712 10.789 ;
     RECT  10.5 2.151 10.812 10.837 ;
     RECT  5.1 2.137 5.592 10.931 ;
     RECT  2.304 10.789 2.712 11.123 ;
     RECT  10.32 10.837 10.812 12.515 ;
     RECT  4.08 12.325 4.104 12.517 ;
     RECT  5.1 10.931 5.412 12.517 ;
     RECT  7.008 9.061 8.112 12.901 ;
     RECT  4.08 12.517 5.412 13.045 ;
     RECT  6.768 12.901 8.112 13.045 ;
     RECT  4.08 13.045 8.28 13.139 ;
     RECT  5.1 13.139 8.28 13.429 ;
     RECT  5.1 13.429 8.376 13.573 ;
     RECT  10.368 12.515 10.812 13.573 ;
     RECT  4.08 13.139 4.104 14.821 ;
     RECT  5.1 13.573 10.812 14.821 ;
     RECT  2.4 11.123 2.712 15.129 ;
     RECT  4.08 14.821 10.812 15.129 ;
     RECT  13.2 2.151 13.512 15.129 ;
     RECT  2.4 15.129 2.52 15.143 ;
     RECT  4.08 15.129 10.62 15.143 ;
     RECT  13.2 15.129 13.32 15.143 ;
     RECT  4.08 15.143 10.344 17.232 ;
     RECT  2.304 6.995 2.4 7.621 ;
     RECT  1.272 7.621 2.4 7.763 ;
     RECT  1.176 7.763 2.4 7.955 ;
     RECT  5.592 9.061 7.008 10.931 ;
     RECT  2.712 12.325 4.08 15.129 ;
     RECT  4.104 12.325 5.1 12.517 ;
     RECT  10.32 12.515 10.368 13.573 ;
     RECT  5.412 12.901 6.768 13.045 ;
     RECT  4.104 13.139 5.1 14.821 ;
  END
END dsfd_rly_66_NW
END LIBRARY
